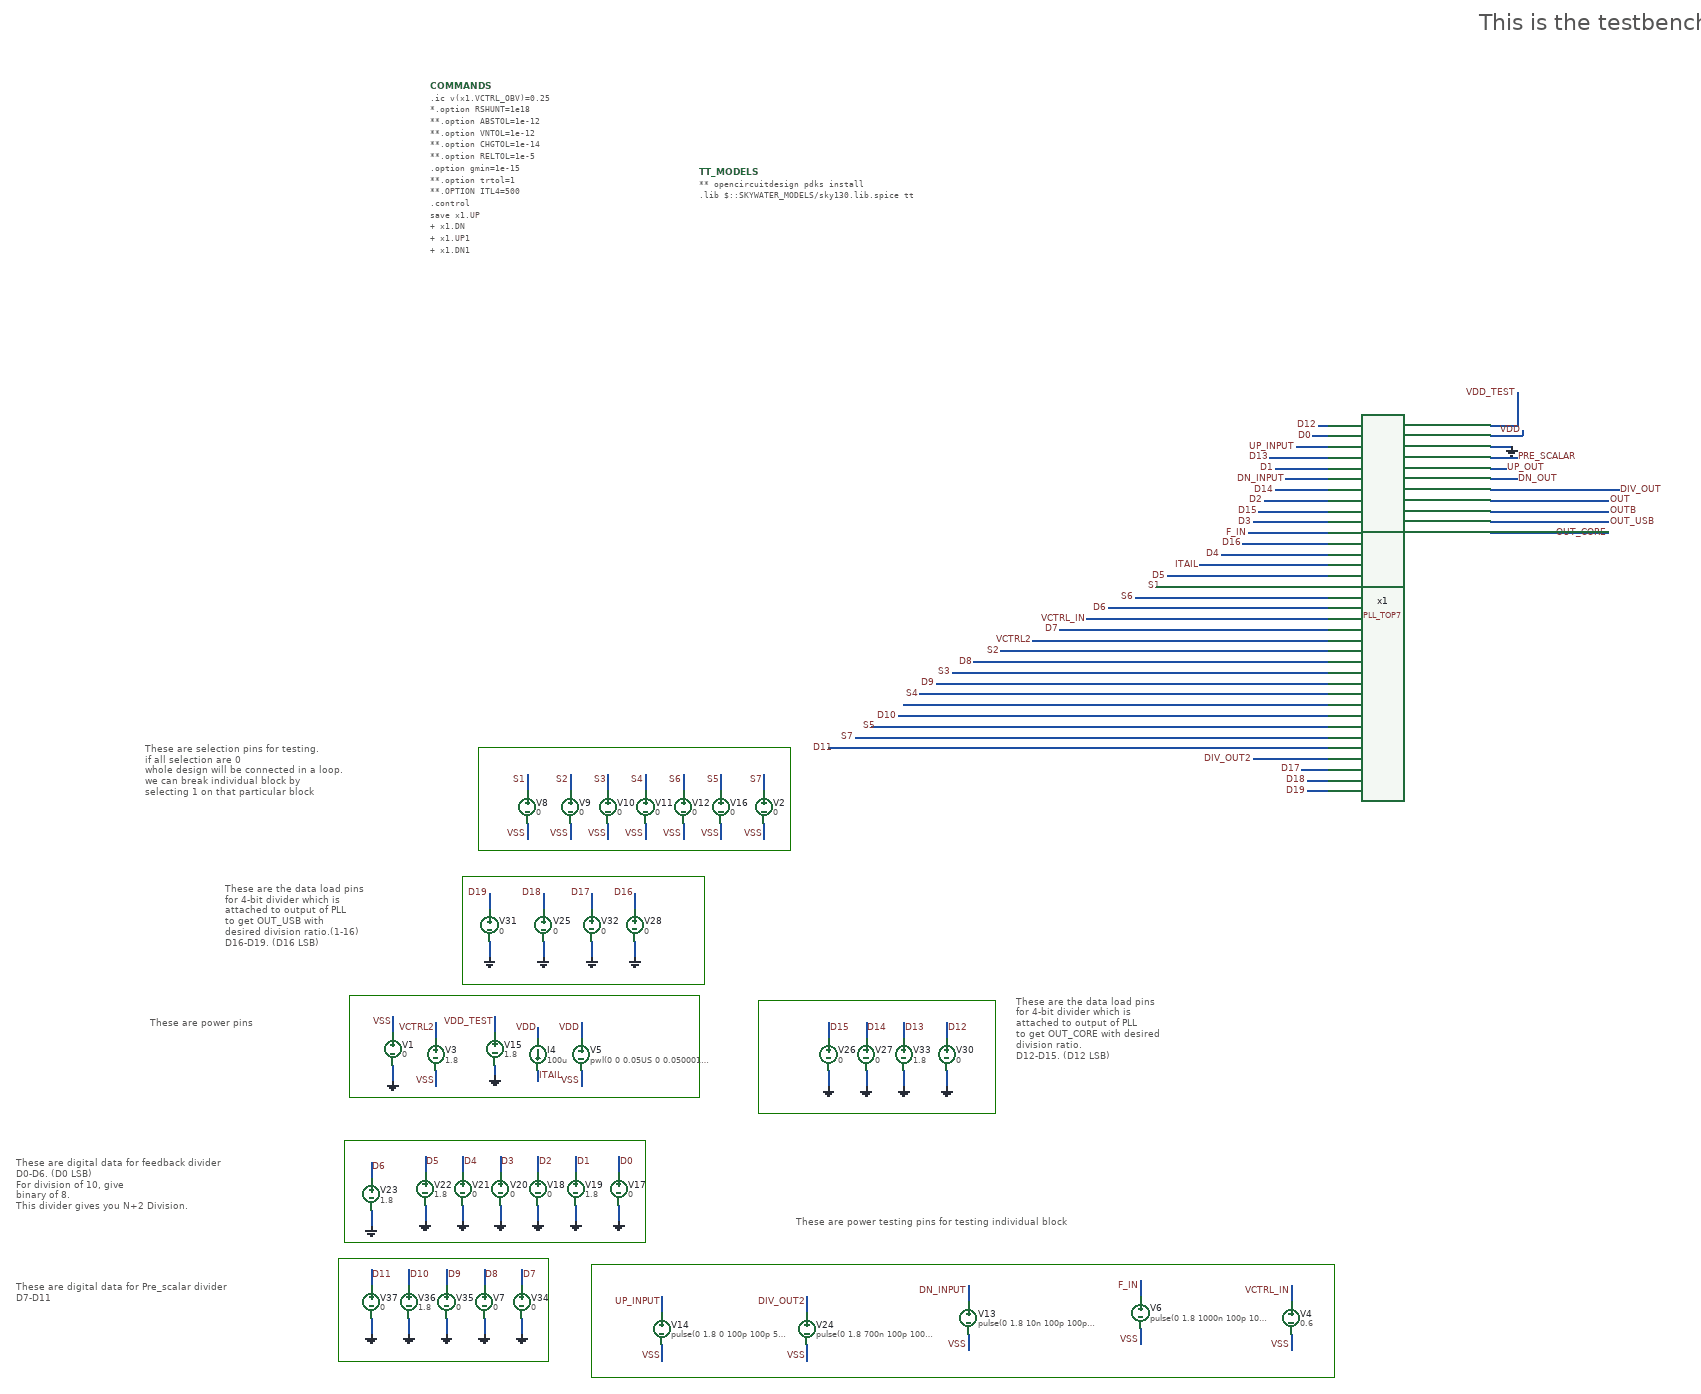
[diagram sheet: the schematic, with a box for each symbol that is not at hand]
v {xschem version=3.4.5 file_version=1.2
}
G {}
K {}
V {}
S {}
E {}
L 4 -2000 280 -2000 470 {}
L 4 -2000 470 -1610 470 {}
L 4 -1610 280 -1610 470 {}
L 4 -2000 280 -1610 280 {}
L 4 -1990 70 -1990 250 {}
L 4 -1990 250 -1430 250 {}
L 4 -1430 60 -1430 250 {}
L 4 -1990 60 -1430 60 {}
L 4 -1990 60 -1990 70 {}
L 4 -1220 -200 -1220 10 {}
L 4 -1220 10 -780 10 {}
L 4 -780 -200 -780 10 {}
L 4 -1220 -200 -780 -200 {}
L 4 -1980 -190 -1980 -20 {}
L 4 -1980 -20 -1330 -20 {}
L 4 -1330 -210 -1330 -20 {}
L 4 -1980 -210 -1330 -210 {}
L 4 -1980 -210 -1980 -200 {}
L 4 -1980 -200 -1980 -190 {}
L 4 -1530 310 -1530 500 {}
L 4 -1530 500 -150 500 {}
L 4 -150 290 -150 500 {}
L 4 -1530 290 -150 290 {}
L 4 -1530 290 -1530 310 {}
L 4 -1740 -650 -1740 -480 {}
L 4 -1740 -480 -1160 -480 {}
L 4 -1160 -670 -1160 -480 {}
L 4 -1740 -670 -1160 -670 {}
L 4 -1740 -670 -1740 -650 {}
L 4 -1770 -430 -1770 -370 {}
L 4 -1770 -430 -1320 -430 {}
L 4 -1320 -430 -1320 -230 {}
L 4 -1770 -230 -1320 -230 {}
L 4 -1770 -370 -1770 -230 {}
B 2 940 -940 1730 -690 {flags=graph
y1=-0.13
y2=2
ypos1=0
ypos2=2
divy=5
subdivy=1
unity=1
x1=5.0161151e-08
x2=6.2952393e-08
divx=5
subdivx=1
xlabmag=1.0
ylabmag=1.0


dataset=-1
unitx=1
logx=0
logy=0
hilight_wave=0


color=4
node=div_out}
B 2 940 -620 1730 -370 {flags=graph
y1=-0.13
y2=2
ypos1=0
ypos2=2
divy=5
subdivy=1
unity=1
x1=5.0161151e-08
x2=6.2952393e-08
divx=5
subdivx=1
xlabmag=1.0
ylabmag=1.0


dataset=-1
unitx=1
logx=0
logy=0
color=4
node=pre_scalar}
B 2 1830 280 2620 530 {flags=graph
y1=-0.029
y2=1.9
ypos1=0
ypos2=2
divy=5
subdivy=1
unity=1
x1=5.0161151e-08
x2=6.2952393e-08
divx=5
subdivx=1
xlabmag=1.0
ylabmag=1.0


dataset=-1
unitx=1
logx=0
logy=0


color=4
node=x1.up}
B 2 940 -350 1730 -100 {flags=graph
y1=-0.023
y2=1.9
ypos1=0
ypos2=2
divy=5
subdivy=1
unity=1
x1=5.0161151e-08
x2=6.2952393e-08
divx=5
subdivx=1
xlabmag=1.0
ylabmag=1.0


dataset=-1
unitx=1
logx=0
logy=0






color=4
node=up_out}
B 2 940 -80 1730 170 {flags=graph

y2=2.2
ypos1=0
ypos2=2
divy=5
subdivy=1
unity=1
x1=5.0161151e-08
x2=6.2952393e-08
divx=5
subdivx=1
xlabmag=1.0
ylabmag=1.0


dataset=-1
unitx=1
logx=0
logy=0





color=4
node=x1.vctrl_obv
y1=0.22}
B 2 1830 20 2620 270 {flags=graph
y1=-0.12
y2=2
ypos1=0
ypos2=2
divy=5
subdivy=1
unity=1
x1=5.0161151e-08
x2=6.2952393e-08
divx=5
subdivx=1
xlabmag=1.0
ylabmag=1.0


dataset=-1
unitx=1
logx=0
logy=0
hilight_wave=0

color=4
node=x1.dn}
B 2 1830 -650 2620 -400 {flags=graph
y1=-0.025
y2=1.9
ypos1=0
ypos2=2
divy=5
subdivy=1
unity=1
x1=5.0161151e-08
x2=6.2952393e-08
divx=5
subdivx=1
xlabmag=1.0
ylabmag=1.0
node=outb
color=4
dataset=-1
unitx=1
logx=0
logy=0
hilight_wave=0}
B 2 1830 -400 2620 -150 {flags=graph
y1=-0.066
y2=1.9
ypos1=0
ypos2=2
divy=5
subdivy=1
unity=1
x1=5.0161151e-08
x2=6.2952393e-08
divx=5
subdivx=1
xlabmag=1.0
ylabmag=1.0
node=out
color=4
dataset=-1
unitx=1
logx=0
logy=0
hilight_wave=0}
B 2 1830 -1150 2620 -900 {flags=graph
y1=-0.05
y2=2
ypos1=0
ypos2=2
divy=5
subdivy=1
unity=1
x1=5.0161151e-08
x2=6.2952393e-08
divx=5
subdivx=1
xlabmag=1.0
ylabmag=1.0


dataset=-1
unitx=1
logx=0
logy=0
hilight_wave=0
color=4
node=out_core}
B 2 1830 -900 2620 -650 {flags=graph
y1=-0.062
y2=1.9
ypos1=0
ypos2=2
divy=5
subdivy=1
unity=1
x1=5.0161151e-08
x2=6.2952393e-08
divx=5
subdivx=1
xlabmag=1.0
ylabmag=1.0


dataset=-1
unitx=1
logx=0
logy=0
hilight_wave=0
color=4
node=out_usb}
T {This is the testbench for testing PLL} 120 -2030 0 0 2 2 { hcenter=true}
T {These are digital data for Pre_scalar divider
D7-D11
} -2600 320 0 0 0.5 0.5 {}
T {These are digital data for feedback divider
D0-D6. (D0 LSB)
For division of 10, give
binary of 8.
This divider gives you N+2 Division.} -2600 90 0 0 0.5 0.5 {}
T {These are power pins
} -2350 -170 0 0 0.5 0.5 {}
T {These are power testing pins for testing individual block
} -1150 200 0 0 0.5 0.5 {}
T {These are the data load pins 
for 4-bit divider which is 
attached to output of PLL
to get OUT_CORE with desired
division ratio. 
D12-D15. (D12 LSB)
} -740 -210 0 0 0.5 0.5 {}
T {These are selection pins for testing. 
if all selection are 0 
whole design will be connected in a loop. 
we can break individual block by 
selecting 1 on that particular block
} -2360 -680 0 0 0.5 0.5 {}
T {These are the data load pins 
for 4-bit divider which is 
attached to output of PLL
to get OUT_USB with
desired division ratio.(1-16)
D16-D19. (D16 LSB)} -2210 -420 0 0 0.5 0.5 {}
N -1900 -80 -1900 -50 {
lab=GND}
N -1900 -170 -1900 -140 {
lab=VSS}
N -1820 -160 -1820 -130 {
lab=VCTRL2}
N -1820 -70 -1820 -40 {
lab=VSS}
N -230 330 -230 360 {
lab=VCTRL_IN}
N -230 420 -230 450 {
lab=VSS}
N -510 320 -510 350 {
lab=F_IN}
N -510 410 -510 440 {
lab=VSS}
N -1630 -150 -1630 -130 {
lab=VDD}
N -1630 -70 -1630 -50 {
lab=ITAIL}
N -1650 -620 -1650 -590 {
lab=S1}
N -1650 -530 -1650 -500 {
lab=VSS}
N -1570 -620 -1570 -590 {
lab=S2}
N -1570 -530 -1570 -500 {
lab=VSS}
N -1500 -620 -1500 -590 {
lab=S3}
N -1500 -530 -1500 -500 {
lab=VSS}
N -1430 -620 -1430 -590 {
lab=S4}
N -1430 -530 -1430 -500 {
lab=VSS}
N -1360 -620 -1360 -590 {
lab=S6}
N -1360 -530 -1360 -500 {
lab=VSS}
N -830 330 -830 360 {
lab=DN_INPUT}
N -830 420 -830 450 {
lab=VSS}
N -1400 350 -1400 380 {
lab=UP_INPUT}
N -1400 440 -1400 470 {
lab=VSS}
N 140 -1190 170 -1190 {
lab=UP_OUT}
N 140 -1170 190 -1170 {
lab=DN_OUT}
N -180 -1270 -160 -1270 {
lab=D12}
N 140 -1210 190 -1210 {
lab=PRE_SCALAR}
N -220 -1230 -160 -1230 {
lab=UP_INPUT}
N -260 -1190 -160 -1190 {
lab=D1}
N -270 -1210 -160 -1210 {
lab=D13}
N -280 -1130 -160 -1130 {
lab=D2}
N -290 -1110 -160 -1110 {
lab=D15}
N -300 -1090 -160 -1090 {
lab=D3}
N -310 -1070 -160 -1070 {
lab=F_IN}
N -320 -1050 -160 -1050 {
lab=D16}
N 140 -1130 360 -1130 {
lab=OUT}
N 140 -1110 360 -1110 {
lab=OUTB}
N -1710 -170 -1710 -140 {
lab=VDD_TEST}
N -1710 -80 -1710 -50 {
lab=GND}
N 200 -1260 200 -1250 {
lab=VDD}
N -360 -1030 -160 -1030 {
lab=D4}
N -1290 -620 -1290 -590 {
lab=S5}
N -1290 -530 -1290 -500 {
lab=VSS}
N 140 -1150 380 -1150 {
lab=DIV_OUT}
N 140 -1090 360 -1090 {
lab=OUT_USB}
N -190 -1250 -160 -1250 {
lab=D0}
N -260 -1150 -160 -1150 {
lab=D14}
N -400 -1010 -160 -1010 {
lab=ITAIL}
N -460 -990 -160 -990 {
lab=D5}
N -480 -970 -160 -970 {
lab=S1}
N -520 -950 -160 -950 {
lab=S6}
N -570 -930 -160 -930 {
lab=D6}
N -610 -910 -160 -910 {
lab=VCTRL_IN}
N -660 -890 -160 -890 {
lab=D7}
N -710 -870 -160 -870 {
lab=VCTRL2}
N -770 -850 -160 -850 {
lab=S2}
N -820 -830 -160 -830 {
lab=D8}
N -860 -810 -160 -810 {
lab=S3}
N -890 -790 -160 -790 {
lab=D9}
N -920 -770 -160 -770 {
lab=S4}
N -950 -750 -160 -750 {
lab=#net1}
N -960 -730 -160 -730 {
lab=D10}
N -1010 -710 -160 -710 {
lab=S5}
N -1040 -690 -160 -690 {
lab=S7}
N -1090 -670 -160 -670 {
lab=D11}
N -1480 90 -1480 120 {
lab=D0}
N -1480 180 -1480 210 {
lab=GND}
N -1560 90 -1560 120 {
lab=D1}
N -1560 180 -1560 210 {
lab=GND}
N -1630 90 -1630 120 {
lab=D2}
N -1630 180 -1630 210 {
lab=GND}
N -1700 90 -1700 120 {
lab=D3}
N -1700 180 -1700 210 {
lab=GND}
N -1770 90 -1770 120 {
lab=D4}
N -1770 180 -1770 210 {
lab=GND}
N -1840 90 -1840 120 {
lab=D5}
N -1840 180 -1840 210 {
lab=GND}
N -1940 100 -1940 130 {
lab=D6}
N -1940 190 -1940 220 {
lab=GND}
N -870 -160 -870 -130 {
lab=D12}
N -870 -70 -870 -40 {
lab=GND}
N -950 -160 -950 -130 {
lab=D13}
N -950 -70 -950 -40 {
lab=GND}
N -1020 -160 -1020 -130 {
lab=D14}
N -1020 -70 -1020 -40 {
lab=GND}
N -1090 -160 -1090 -130 {
lab=D15}
N -1090 -70 -1090 -40 {
lab=GND}
N 140 -1270 190 -1270 {
lab=VDD_TEST}
N 190 -1330 190 -1270 {
lab=VDD_TEST}
N -1210 -620 -1210 -590 {
lab=S7}
N -1210 -530 -1210 -500 {
lab=VSS}
N -1550 -160 -1550 -130 {
lab=VDD}
N -1550 -70 -1550 -40 {
lab=VSS}
N -1660 300 -1660 330 {
lab=D7}
N -1660 390 -1660 420 {
lab=GND}
N -1730 300 -1730 330 {
lab=D8}
N -1730 390 -1730 420 {
lab=GND}
N -1800 300 -1800 330 {
lab=D9}
N -1800 390 -1800 420 {
lab=GND}
N -1870 300 -1870 330 {
lab=D10}
N -1870 390 -1870 420 {
lab=GND}
N -1940 300 -1940 330 {
lab=D11}
N -1940 390 -1940 420 {
lab=GND}
N -1130 350 -1130 380 {
lab=DIV_OUT2}
N -1130 440 -1130 470 {
lab=VSS}
N -300 -650 -160 -650 {
lab=DIV_OUT2}
N 160 -1230 180 -1230 {
lab=GND}
N -200 -590 -160 -590 {
lab=D19}
N -200 -610 -160 -610 {
lab=D18}
N -210 -630 -160 -630 {
lab=D17}
N -240 -1170 -160 -1170 {
lab=DN_INPUT}
N 140 -1230 160 -1230 {
lab=GND}
N 140 -1070 360 -1070 {
lab=OUT_CORE}
N -1720 -310 -1720 -280 {
lab=GND}
N -1720 -400 -1720 -370 {
lab=D19}
N -1620 -310 -1620 -280 {
lab=GND}
N -1620 -400 -1620 -370 {
lab=D18}
N -1530 -310 -1530 -280 {
lab=GND}
N -1530 -400 -1530 -370 {
lab=D17}
N -1450 -310 -1450 -280 {
lab=GND}
N -1450 -400 -1450 -370 {
lab=D16}
N 140 -1250 200 -1250 {
lab=VDD}
C {devices/code_shown.sym} -1830 -1900 0 1 {name=COMMANDS only_toplevel=true
value="
.ic v(x1.VCTRL_OBV)=0.25
*.option RSHUNT=1e18
**.option ABSTOL=1e-12
**.option VNTOL=1e-12
**.option CHGTOL=1e-14
**.option RELTOL=1e-5
.option gmin=1e-15
**.option trtol=1
**.OPTION ITL4=500
.control
save x1.UP
+ x1.DN
+ x1.UP1
+ x1.DN1
+ x1.VCTRL_OBV
+ x1.OUT
+ x1.OUTB
+ x1.OUTD
+ x1.IN_DIV
+ x1.OUT11
+ x1.UP_OUT
+ x1.pre_out
+ x1.OUTA1
+ x1.OUTA2
+ OUT1
+ OUT
+ OUTB
+ PRE_SCALAR
+ x1.UP_OUT
+ x1.OUT_D
+ x1.OUT01
+ x1.MUFTA2
+ x1.MUFTA
+ DN_OUT
+ UP_OUT
+ DIV_OUT
+ ITAIL
+ x1.ITAIL_SINK
+ x1.ITAIL_SRC
+ OUT_USB
+ OUT_CORE
+ v1#branch
tran 500n 100u

write "TB_TOP_MUX_F7_sch.raw"
.endc
"}
C {devices/vsource.sym} -1900 -110 0 0 {name=V1 value=0}
C {devices/gnd.sym} -1900 -50 0 0 {name=l1 lab=GND}
C {devices/lab_wire.sym} -1900 -160 0 0 {name=p1 sig_type=std_logic lab=VSS}
C {devices/lab_wire.sym} -1820 -150 0 0 {name=p6 sig_type=std_logic lab=VCTRL2}
C {devices/lab_wire.sym} -1820 -50 0 0 {name=p9 sig_type=std_logic lab=VSS}
C {devices/vsource.sym} -230 390 0 0 {name=V4 value=0.6}
C {devices/lab_wire.sym} -230 340 0 0 {name=p3 sig_type=std_logic lab=VCTRL_IN}
C {devices/lab_wire.sym} -230 440 0 0 {name=p5 sig_type=std_logic lab=VSS}
C {devices/vsource.sym} -510 380 0 0 {name=V6 value="pulse(0 1.8 1000n 100p 100p 50n 100n)"}
C {devices/lab_wire.sym} -510 430 0 0 {name=p40 sig_type=std_logic lab=VSS}
C {devices/lab_wire.sym} -510 330 0 0 {name=p41 sig_type=std_logic lab=F_IN}
C {devices/isource.sym} -1630 -100 0 0 {name=I4 value=100u}
C {devices/lab_wire.sym} -1630 -150 0 0 {name=p29 sig_type=std_logic lab=VDD}
C {devices/lab_wire.sym} -1630 -60 2 0 {name=p36 sig_type=std_logic lab=ITAIL}
C {devices/vsource.sym} -1650 -560 0 0 {name=V8 value=0}
C {devices/lab_wire.sym} -1650 -610 0 0 {name=p31 sig_type=std_logic lab=S1
value=3.3}
C {devices/lab_wire.sym} -1650 -510 0 0 {name=p32 sig_type=std_logic lab=VSS
value=3.3}
C {devices/vsource.sym} -1570 -560 0 0 {name=V9 value=0}
C {devices/lab_wire.sym} -1570 -610 0 0 {name=p33 sig_type=std_logic lab=S2
value=3.3}
C {devices/lab_wire.sym} -1570 -510 0 0 {name=p34 sig_type=std_logic lab=VSS
value=3.3}
C {devices/vsource.sym} -1500 -560 0 0 {name=V10 value=0}
C {devices/lab_wire.sym} -1500 -610 0 0 {name=p37 sig_type=std_logic lab=S3
value=3.3}
C {devices/lab_wire.sym} -1500 -510 0 0 {name=p39 sig_type=std_logic lab=VSS
value=3.3}
C {devices/vsource.sym} -1430 -560 0 0 {name=V11 value=0}
C {devices/lab_wire.sym} -1430 -610 0 0 {name=p42 sig_type=std_logic lab=S4
value=3.3}
C {devices/lab_wire.sym} -1430 -510 0 0 {name=p43 sig_type=std_logic lab=VSS
value=3.3}
C {devices/vsource.sym} -1360 -560 0 0 {name=V12 value=0}
C {devices/lab_wire.sym} -1360 -610 0 0 {name=p44 sig_type=std_logic lab=S6
value=3.3}
C {devices/lab_wire.sym} -1360 -510 0 0 {name=p45 sig_type=std_logic lab=VSS
value=3.3}
C {devices/vsource.sym} -830 390 0 0 {name=V13 value="pulse(0 1.8 10n 100p 100p 500n 1000n)"}
C {devices/lab_wire.sym} -830 440 0 0 {name=p48 sig_type=std_logic lab=VSS}
C {devices/lab_wire.sym} -830 340 0 0 {name=p49 sig_type=std_logic lab=DN_INPUT}
C {devices/vsource.sym} -1400 410 0 0 {name=V14 value="pulse(0 1.8 0 100p 100p 500n 1000n)"}
C {devices/lab_wire.sym} -1400 460 0 0 {name=p50 sig_type=std_logic lab=VSS}
C {devices/lab_wire.sym} -1400 360 0 0 {name=p51 sig_type=std_logic lab=UP_INPUT}
C {devices/lab_wire.sym} -220 -1230 0 0 {name=p52 sig_type=std_logic lab=UP_INPUT}
C {devices/lab_wire.sym} -240 -1170 0 0 {name=p53 sig_type=std_logic lab=DN_INPUT}
C {devices/lab_wire.sym} 190 -1210 2 0 {name=p54 sig_type=std_logic lab=PRE_SCALAR
}
C {devices/lab_wire.sym} -310 -1070 0 0 {name=p55 sig_type=std_logic lab=F_IN}
C {devices/lab_wire.sym} -400 -1010 0 0 {name=p57 sig_type=std_logic lab=ITAIL
}
C {devices/lab_wire.sym} -610 -910 0 0 {name=p59 sig_type=std_logic lab=VCTRL_IN}
C {devices/lab_wire.sym} -710 -870 0 0 {name=p60 sig_type=std_logic lab=VCTRL2}
C {devices/lab_wire.sym} -470 -970 0 0 {name=p61 sig_type=std_logic lab=S1}
C {devices/lab_wire.sym} -770 -850 0 0 {name=p62 sig_type=std_logic lab=S2}
C {devices/lab_wire.sym} -860 -810 0 0 {name=p63 sig_type=std_logic lab=S3}
C {devices/lab_wire.sym} -920 -770 0 0 {name=p64 sig_type=std_logic lab=S4}
C {devices/lab_wire.sym} -1000 -710 0 0 {name=p65 sig_type=std_logic lab=S5}
C {devices/lab_wire.sym} 200 -1260 1 0 {name=p67 sig_type=std_logic lab=VDD}
C {devices/lab_wire.sym} 170 -1190 2 0 {name=p68 sig_type=std_logic lab=UP_OUT}
C {devices/lab_wire.sym} 190 -1170 2 0 {name=p69 sig_type=std_logic lab=DN_OUT}
C {devices/lab_wire.sym} 360 -1130 2 0 {name=p76 sig_type=std_logic lab=OUT}
C {devices/lab_wire.sym} 360 -1110 2 0 {name=p77 sig_type=std_logic lab=OUTB}
C {devices/lab_wire.sym} -1710 -160 0 0 {name=p78 sig_type=std_logic lab=VDD_TEST}
C {devices/lab_wire.sym} -520 -950 0 0 {name=p82 sig_type=std_logic lab=S6}
C {devices/vsource.sym} -1290 -560 0 0 {name=V16 value=0}
C {devices/lab_wire.sym} -1290 -610 0 0 {name=p86 sig_type=std_logic lab=S5
value=3.3}
C {devices/lab_wire.sym} -1290 -510 0 0 {name=p87 sig_type=std_logic lab=VSS
value=3.3}
C {devices/lab_wire.sym} 380 -1150 2 0 {name=p2 sig_type=std_logic lab=DIV_OUT}
C {devices/lab_wire.sym} 260 -1070 2 0 {name=p7 sig_type=std_logic lab=OUT_CORE}
C {devices/lab_wire.sym} -1040 -690 0 0 {name=p10 sig_type=std_logic lab=S7}
C {devices/lab_wire.sym} -190 -1250 0 0 {name=p11 sig_type=std_logic lab=D0}
C {devices/lab_wire.sym} -260 -1190 0 0 {name=p12 sig_type=std_logic lab=D1}
C {devices/lab_wire.sym} -280 -1130 0 0 {name=p13 sig_type=std_logic lab=D2}
C {devices/lab_wire.sym} -300 -1090 0 0 {name=p14 sig_type=std_logic lab=D3}
C {devices/lab_wire.sym} -360 -1030 0 0 {name=p15 sig_type=std_logic lab=D4}
C {devices/lab_wire.sym} -460 -990 0 0 {name=p16 sig_type=std_logic lab=D5}
C {devices/lab_wire.sym} -570 -930 0 0 {name=p17 sig_type=std_logic lab=D6}
C {devices/lab_wire.sym} -660 -890 0 0 {name=p18 sig_type=std_logic lab=D7}
C {devices/lab_wire.sym} -820 -830 0 0 {name=p19 sig_type=std_logic lab=D8}
C {devices/lab_wire.sym} -890 -790 0 0 {name=p20 sig_type=std_logic lab=D9}
C {devices/lab_wire.sym} -960 -730 0 0 {name=p21 sig_type=std_logic lab=D10}
C {devices/lab_wire.sym} -1080 -670 0 0 {name=p22 sig_type=std_logic lab=D11}
C {devices/lab_wire.sym} -180 -1270 0 0 {name=p24 sig_type=std_logic lab=D12}
C {devices/lab_wire.sym} -270 -1210 0 0 {name=p25 sig_type=std_logic lab=D13}
C {devices/lab_wire.sym} -260 -1150 0 0 {name=p26 sig_type=std_logic lab=D14}
C {devices/lab_wire.sym} -290 -1110 0 0 {name=p27 sig_type=std_logic lab=D15}
C {devices/lab_wire.sym} -320 -1050 0 0 {name=p28 sig_type=std_logic lab=D16}
C {devices/vsource.sym} -1480 150 0 1 {name=V17 value=0}
C {devices/lab_wire.sym} -1480 100 0 1 {name=p56 sig_type=std_logic lab=D0}
C {devices/lab_wire.sym} -1560 100 0 1 {name=p71 sig_type=std_logic lab=D1}
C {devices/lab_wire.sym} -1630 100 0 1 {name=p73 sig_type=std_logic lab=D2}
C {devices/lab_wire.sym} -1700 100 0 1 {name=p75 sig_type=std_logic lab=D3}
C {devices/lab_wire.sym} -1770 100 0 1 {name=p81 sig_type=std_logic lab=D4}
C {devices/lab_wire.sym} -1840 100 0 1 {name=p100 sig_type=std_logic lab=D5}
C {devices/lab_wire.sym} -1940 110 0 1 {name=p102 sig_type=std_logic lab=D6}
C {devices/lab_wire.sym} -870 -150 0 1 {name=p114 sig_type=std_logic lab=D12}
C {devices/lab_wire.sym} -950 -150 0 1 {name=p116 sig_type=std_logic lab=D13}
C {devices/lab_wire.sym} -1020 -150 0 1 {name=p118 sig_type=std_logic lab=D14}
C {devices/lab_wire.sym} -1090 -150 0 1 {name=p120 sig_type=std_logic lab=D15}
C {devices/lab_wire.sym} 190 -1330 1 0 {name=p23 sig_type=std_logic lab=VDD_TEST}
C {devices/vsource.sym} -1210 -560 0 0 {name=V2 value=0}
C {devices/lab_wire.sym} -1210 -610 0 0 {name=p4 sig_type=std_logic lab=S7
value=3.3}
C {devices/lab_wire.sym} -1210 -510 0 0 {name=p8 sig_type=std_logic lab=VSS
value=3.3}
C {devices/vsource.sym} -1550 -100 0 0 {name=V5 value="pwl(0 0 0.05US 0 0.050001US 1.8)"}
C {devices/lab_wire.sym} -1550 -150 0 0 {name=p38 sig_type=std_logic lab=VDD}
C {devices/lab_wire.sym} -1550 -50 0 0 {name=p46 sig_type=std_logic lab=VSS}
C {devices/lab_wire.sym} -1660 310 0 1 {name=p47 sig_type=std_logic lab=D7}
C {devices/lab_wire.sym} -1730 310 0 1 {name=p89 sig_type=std_logic lab=D8}
C {devices/vsource.sym} -1800 360 0 1 {name=V35 value=0}
C {devices/lab_wire.sym} -1800 310 0 1 {name=p92 sig_type=std_logic lab=D9}
C {devices/lab_wire.sym} -1870 310 0 1 {name=p94 sig_type=std_logic lab=D10}
C {devices/vsource.sym} -1940 360 0 1 {name=V37 value=0}
C {devices/lab_wire.sym} -1940 310 0 1 {name=p96 sig_type=std_logic lab=D11}
C {devices/vsource.sym} -1130 410 0 0 {name=V24 value="pulse(0 1.8 700n 100p 100p 500n 1000n)"}
C {devices/lab_wire.sym} -1130 460 0 0 {name=p98 sig_type=std_logic lab=VSS}
C {devices/lab_wire.sym} -1130 360 0 0 {name=p99 sig_type=std_logic lab=DIV_OUT2}
C {devices/lab_wire.sym} -300 -650 3 0 {name=p104 sig_type=std_logic lab=DIV_OUT2}
C {devices/lab_wire.sym} -210 -630 0 0 {name=p105 sig_type=std_logic lab=D17}
C {devices/lab_wire.sym} -200 -610 0 0 {name=p106 sig_type=std_logic lab=D18}
C {devices/lab_wire.sym} -200 -590 0 0 {name=p107 sig_type=std_logic lab=D19}
C {devices/code.sym} -1330 -1740 0 0 {name=TT_MODELS
only_toplevel=true
format="tcleval( @value )"
value="
** opencircuitdesign pdks install
.lib $::SKYWATER_MODELS/sky130.lib.spice tt

"
spice_ignore=false}
C {devices/vsource.sym} -1700 150 0 1 {name=V20 value=0}
C {devices/vsource.sym} -1840 150 0 1 {name=V22 value=1.8}
C {devices/vsource.sym} -1820 -100 0 1 {name=V3 value=1.8}
C {devices/vsource.sym} -1710 -110 0 1 {name=V15 value=1.8}
C {devices/vsource.sym} -1870 360 0 1 {name=V36 value=1.8}
C {devices/gnd.sym} -1870 420 0 0 {name=l6 lab=GND}
C {devices/gnd.sym} -1940 420 0 0 {name=l7 lab=GND}
C {devices/gnd.sym} -1800 420 0 0 {name=l8 lab=GND}
C {devices/gnd.sym} -1730 420 0 0 {name=l9 lab=GND}
C {devices/gnd.sym} -1660 420 0 0 {name=l10 lab=GND}
C {devices/gnd.sym} -1940 220 0 0 {name=l11 lab=GND}
C {devices/gnd.sym} -1840 210 0 0 {name=l12 lab=GND}
C {devices/gnd.sym} -1770 210 0 0 {name=l13 lab=GND}
C {devices/gnd.sym} -1700 210 0 0 {name=l14 lab=GND}
C {devices/gnd.sym} -1630 210 0 0 {name=l15 lab=GND}
C {devices/gnd.sym} -1560 210 0 0 {name=l16 lab=GND}
C {devices/gnd.sym} -1480 210 0 0 {name=l17 lab=GND}
C {devices/gnd.sym} -1090 -40 0 0 {name=l19 lab=GND}
C {devices/gnd.sym} -1020 -40 0 0 {name=l20 lab=GND}
C {devices/gnd.sym} -950 -40 0 0 {name=l21 lab=GND}
C {devices/gnd.sym} -870 -40 0 0 {name=l22 lab=GND}
C {devices/gnd.sym} -1710 -60 0 0 {name=l23 lab=GND}
C {devices/launcher.sym} 140 90 0 0 {name=h17 
descr="Load waves" 
tclcommand="
xschem raw_read $netlist_dir/[file tail [file rootname [xschem get current_name]]].raw tran

"
}
C {devices/vsource.sym} -1730 360 0 1 {name=V7 value=0}
C {devices/vsource.sym} -1660 360 0 1 {name=V34 value=0}
C {devices/vsource.sym} -1770 150 0 1 {name=V21 value=0}
C {devices/vsource.sym} -1940 160 0 1 {name=V23 value=1.8}
C {devices/title.sym} -1160 870 0 0 {name=l24 author="ATIF|AZEEM|SALEH|ROHAIL"}
C {devices/lab_wire.sym} 360 -1090 2 0 {name=p30 sig_type=std_logic lab=OUT_USB}
C {devices/gnd.sym} -1720 -280 0 0 {name=l25 lab=GND}
C {devices/lab_wire.sym} -1720 -400 0 0 {name=p35 sig_type=std_logic lab=D19}
C {devices/gnd.sym} -1620 -280 0 0 {name=l26 lab=GND}
C {devices/gnd.sym} -1530 -280 0 0 {name=l27 lab=GND}
C {devices/gnd.sym} -1450 -280 0 0 {name=l28 lab=GND}
C {devices/lab_wire.sym} -1620 -400 0 0 {name=p58 sig_type=std_logic lab=D18}
C {devices/lab_wire.sym} -1530 -400 0 0 {name=p70 sig_type=std_logic lab=D17}
C {devices/lab_wire.sym} -1450 -400 0 0 {name=p72 sig_type=std_logic lab=D16
}
C {devices/vsource.sym} -1620 -340 0 0 {name=V25 value=0}
C {devices/vsource.sym} -1090 -100 0 1 {name=V26 value=0}
C {devices/vsource.sym} -1720 -340 0 0 {name=V31 value=0}
C {devices/vsource.sym} -1450 -340 0 1 {name=V28 value=0}
C {devices/gnd.sym} 180 -1230 3 0 {name=l2 lab=GND}
C {devices/vsource.sym} -1020 -100 0 1 {name=V27 value=0}
C {devices/vsource.sym} -870 -100 0 1 {name=V30 value=0}
C {devices/vsource.sym} -1530 -340 0 1 {name=V32 value=0}
C {devices/vsource.sym} -1630 150 0 1 {name=V18 value=0}
C {devices/vsource.sym} -1560 150 0 1 {name=V19 value=1.8}
C {devices/vsource.sym} -950 -100 0 1 {name=V33 value=1.8}
C {PLL_TOP7.sym} 0 -860 0 0 {name=x1}
